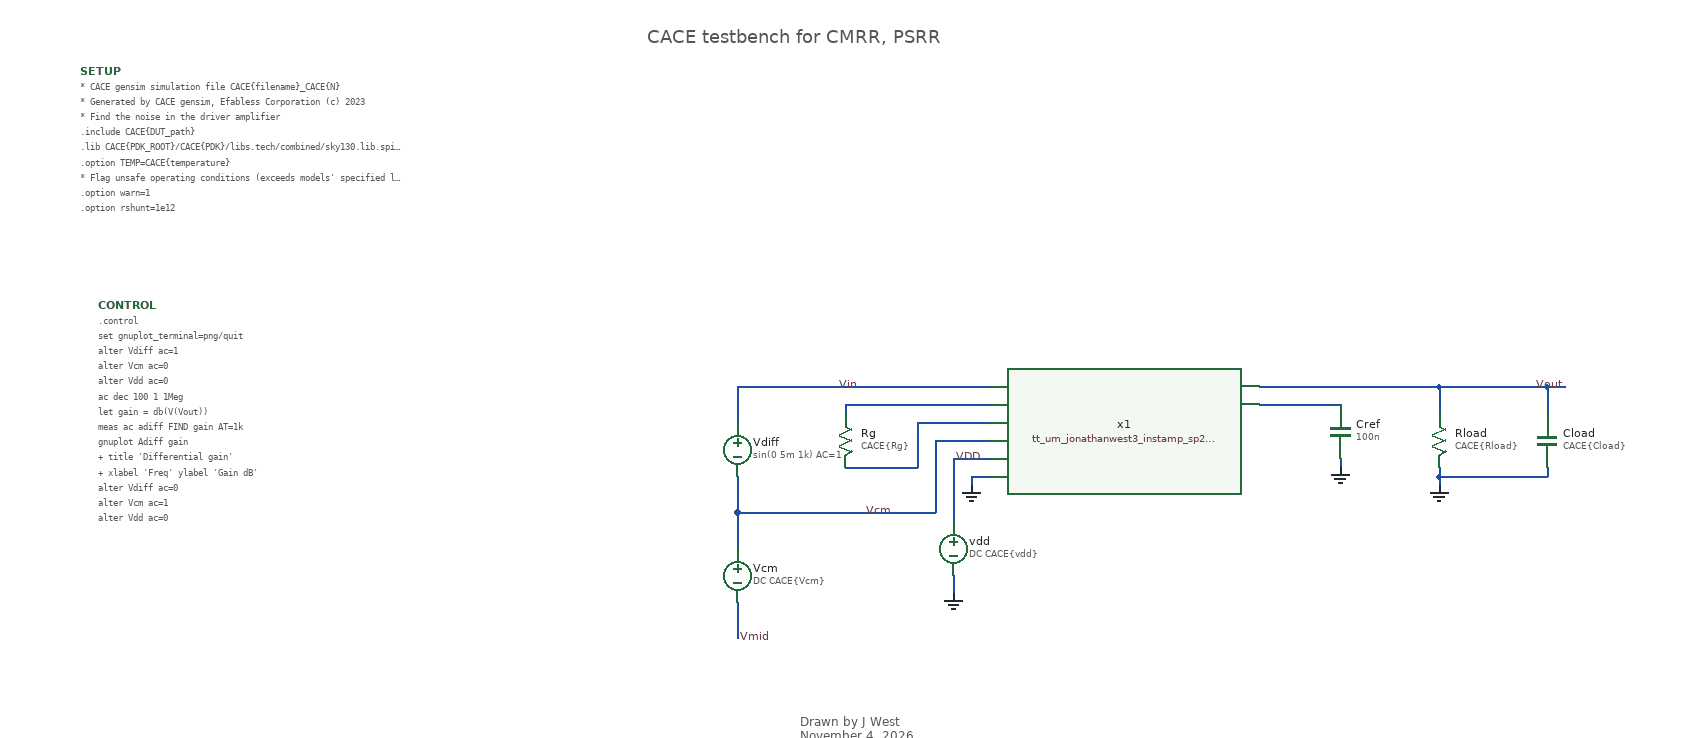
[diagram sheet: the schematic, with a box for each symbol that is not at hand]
v {xschem version=3.4.8RC file_version=1.3}
G {}
K {}
V {}
S {}
F {}
E {}
T {CACE testbench for CMRR, PSRR} -390 -640 0 0 0.6 0.6 {}
T {Drawn by J West
November 4, 2026
Revision 0
} -220 120 0 0 0.4 0.4 {}
N 610 -240 630 -240 {
lab=Vout}
N -170 -220 -170 -210 {lab=#net1}
N -170 -220 -10 -220 {lab=#net1}
N -170 -150 -90 -150 {lab=#net2}
N -90 -180 -90 -150 {lab=#net2}
N -70 -160 -70 -100 {lab=Vcm}
N -290 -100 -70 -100 {lab=Vcm}
N 290 -220 380 -220 {lab=#net3}
N 380 -160 380 -150 {lab=GND}
N -50 -30 -50 -10 {lab=GND}
N -50 -110 -50 -90 {lab=VDD}
N -290 0 -290 10 {lab=Vmid}
N -290 -240 -10 -240 {lab=Vin}
N -50 -160 -10 -160 {lab=VDD}
N 490 -140 490 -130 {lab=GND}
N 490 -150 490 -140 {lab=GND}
N 540 -140 610 -140 {lab=GND}
N 610 -150 610 -140 {lab=GND}
N 610 -240 610 -210 {lab=Vout}
N 490 -240 490 -210 {lab=Vout}
N -290 -240 -290 -200 {lab=Vin}
N -290 -140 -290 -100 {lab=Vcm}
N -290 -100 -290 -60 {lab=Vcm}
N 540 -240 610 -240 {
lab=Vout}
N 290 -240 490 -240 {
lab=Vout}
N -50 -160 -50 -110 {lab=VDD}
N 490 -240 540 -240 {lab=Vout}
N 490 -140 540 -140 {lab=GND}
N -290 10 -290 40 {lab=Vmid}
N -90 -200 -90 -180 {lab=#net2}
N -90 -200 -10 -200 {lab=#net2}
N -70 -180 -70 -160 {lab=Vcm}
N -70 -180 -10 -180 {lab=Vcm}
N -30 -140 -30 -130 {lab=GND}
N -30 -140 -10 -140 {lab=GND}
C {devices/vsource.sym} -290 -30 0 0 {name=Vcm value="DC CACE\{Vcm\}" savecurrent=false}
C {devices/lab_wire.sym} 630 -240 0 0 {name=p25 sig_type=std_logic lab=Vout}
C {devices/vsource.sym} -50 -60 0 0 {name=vdd value="DC CACE\{vdd\}" savecurrent=false}
C {devices/code_shown.sym} -1000 -330 0 0 {name=CONTROL only_toplevel=false value=".control
set gnuplot_terminal=png/quit
alter Vdiff ac=1
alter Vcm ac=0
alter Vdd ac=0
ac dec 100 1 1Meg
let gain = db(V(Vout))
meas ac adiff FIND gain AT=1k

gnuplot Adiff gain
+ title 'Differential gain'
+ xlabel 'Freq' ylabel 'Gain dB'

alter Vdiff ac=0
alter Vcm ac=1
alter Vdd ac=0
ac dec 100 1 1Meg
let gain = db(V(Vout))
meas ac acm FIND gain AT=1k

gnuplot Acm gain
+ title 'Common mode gain'
+ xlabel 'Freq' ylabel 'Gain dB'

alter Vdiff ac=0
alter Vcm ac=0
alter Vdd ac=1
ac dec 100 1 1Meg
let gain = db(V(Vout))
meas ac avdd FIND gain AT=1k

gnuplot Avdd gain
+ title 'Power supply gain'
+ xlabel 'Freq' ylabel 'Gain dB'

let CMRR = ac1.Adiff-ac2.Acm
let PSRR = ac1.Adiff-Avdd
echo $&CMRR $&PSRR > CACE\{simpath\}/CACE\{filename\}_CACE\{N\}.data

quit
.endc
"}
C {devices/code_shown.sym} -1020 -590 0 0 {name=SETUP only_toplevel=false value="* CACE gensim simulation file CACE\{filename\}_CACE\{N\}
* Generated by CACE gensim, Efabless Corporation (c) 2023
* Find the noise in the driver amplifier

.include CACE\{DUT_path\}

.lib CACE\{PDK_ROOT\}/CACE\{PDK\}/libs.tech/combined/sky130.lib.spice CACE\{corner\}

.option TEMP=CACE\{temperature\}
* Flag unsafe operating conditions (exceeds models' specified limits)
.option warn=1
.option rshunt=1e12
"}
C {devices/lab_wire.sym} -150 -100 0 1 {name=p4 sig_type=std_logic lab=Vcm}
C {devices/res.sym} -170 -180 0 0 {name=Rg
value=CACE\{Rg\}
device=resistor}
C {capa.sym} 380 -190 0 0 {name=Cref
m=1
value=100n
footprint=1206
device="ceramic capacitor"}
C {devices/gnd.sym} 380 -150 0 0 {name=l2 lab=GND}
C {devices/gnd.sym} -50 -10 0 0 {name=l1 lab=GND}
C {devices/gnd.sym} -30 -130 0 0 {name=l5 lab=GND}
C {devices/lab_wire.sym} -50 -160 0 1 {name=p5 sig_type=std_logic lab=VDD}
C {devices/lab_wire.sym} -180 -240 0 1 {name=p6 sig_type=std_logic lab=Vin}
C {devices/res.sym} 490 -180 0 0 {name=Rload
value=CACE\{Rload\}
device=resistor}
C {capa.sym} 610 -180 0 0 {name=Cload
m=1
value=CACE\{Cload\}
footprint=1206
device="ceramic capacitor"}
C {devices/gnd.sym} 490 -130 0 0 {name=l3 lab=GND}
C {vsource.sym} -290 -170 0 0 {name=Vdiff value="sin(0 5m 1k) AC=1"}
C {devices/lab_wire.sym} -290 40 0 1 {name=p2 sig_type=std_logic lab=Vmid}
C {tt_um_jonathanwest3_instamp_sp2026.sym} 140 10 0 0 {name=x1}
